# OpenTallas memory compiler (tools/mem_compiler), ASAP7 abstract view, track-aligned v2 (build_aligned_v2.py)
VERSION 5.7 ;
BUSBITCHARS "[]" ;
DIVIDERCHAR "/" ;
PROPERTYDEFINITIONS
  MACRO width INTEGER ;
  MACRO depth INTEGER ;
  MACRO banks INTEGER ;
END PROPERTYDEFINITIONS
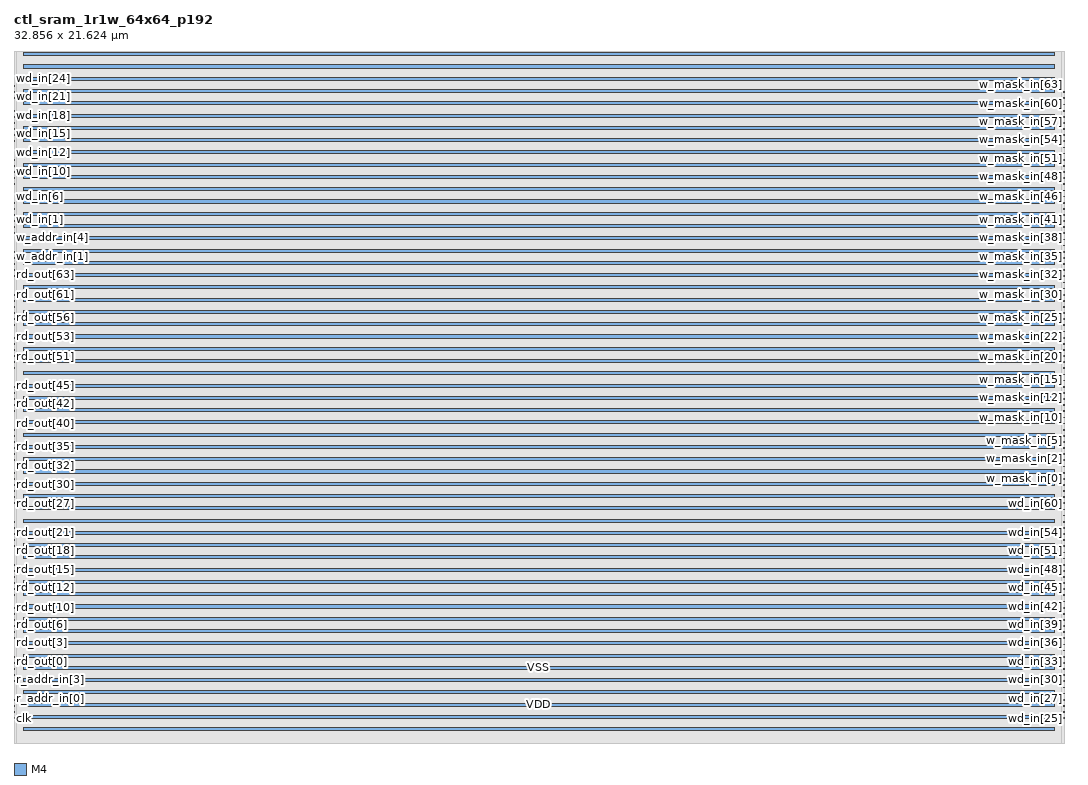
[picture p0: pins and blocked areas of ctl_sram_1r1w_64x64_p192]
MACRO ctl_sram_1r1w_64x64_p192
  PROPERTY width 64 ;
  PROPERTY depth 64 ;
  PROPERTY banks 1 ;
  FOREIGN ctl_sram_1r1w_64x64_p192 0 0 ;
  SYMMETRY X Y ;
  SIZE 32.856 BY 21.624 ;
  CLASS BLOCK ;
  PIN clk
    DIRECTION INPUT ;
    USE CLOCK ;
    SHAPE ABUTMENT ;
    PORT
      LAYER M4 ;
      RECT 0.000 0.768 0.024 0.792 ;
    END
  END clk
  PIN r_ce_in
    DIRECTION INPUT ;
    USE SIGNAL ;
    SHAPE ABUTMENT ;
    PORT
      LAYER M4 ;
      RECT 0.000 0.960 0.024 0.984 ;
    END
  END r_ce_in
  PIN r_addr_in[0]
    DIRECTION INPUT ;
    USE SIGNAL ;
    SHAPE ABUTMENT ;
    PORT
      LAYER M4 ;
      RECT 0.000 1.152 0.024 1.176 ;
    END
  END r_addr_in[0]
  PIN r_addr_in[1]
    DIRECTION INPUT ;
    USE SIGNAL ;
    SHAPE ABUTMENT ;
    PORT
      LAYER M4 ;
      RECT 0.000 1.344 0.024 1.368 ;
    END
  END r_addr_in[1]
  PIN r_addr_in[2]
    DIRECTION INPUT ;
    USE SIGNAL ;
    SHAPE ABUTMENT ;
    PORT
      LAYER M4 ;
      RECT 0.000 1.536 0.024 1.560 ;
    END
  END r_addr_in[2]
  PIN r_addr_in[3]
    DIRECTION INPUT ;
    USE SIGNAL ;
    SHAPE ABUTMENT ;
    PORT
      LAYER M4 ;
      RECT 0.000 1.728 0.024 1.752 ;
    END
  END r_addr_in[3]
  PIN r_addr_in[4]
    DIRECTION INPUT ;
    USE SIGNAL ;
    SHAPE ABUTMENT ;
    PORT
      LAYER M4 ;
      RECT 0.000 1.920 0.024 1.944 ;
    END
  END r_addr_in[4]
  PIN r_addr_in[5]
    DIRECTION INPUT ;
    USE SIGNAL ;
    SHAPE ABUTMENT ;
    PORT
      LAYER M4 ;
      RECT 0.000 2.112 0.024 2.136 ;
    END
  END r_addr_in[5]
  PIN rd_out[0]
    DIRECTION OUTPUT ;
    USE SIGNAL ;
    SHAPE ABUTMENT ;
    PORT
      LAYER M4 ;
      RECT 0.000 2.304 0.024 2.328 ;
    END
  END rd_out[0]
  PIN rd_out[1]
    DIRECTION OUTPUT ;
    USE SIGNAL ;
    SHAPE ABUTMENT ;
    PORT
      LAYER M4 ;
      RECT 0.000 2.496 0.024 2.520 ;
    END
  END rd_out[1]
  PIN rd_out[2]
    DIRECTION OUTPUT ;
    USE SIGNAL ;
    SHAPE ABUTMENT ;
    PORT
      LAYER M4 ;
      RECT 0.000 2.688 0.024 2.712 ;
    END
  END rd_out[2]
  PIN rd_out[3]
    DIRECTION OUTPUT ;
    USE SIGNAL ;
    SHAPE ABUTMENT ;
    PORT
      LAYER M4 ;
      RECT 0.000 2.880 0.024 2.904 ;
    END
  END rd_out[3]
  PIN rd_out[4]
    DIRECTION OUTPUT ;
    USE SIGNAL ;
    SHAPE ABUTMENT ;
    PORT
      LAYER M4 ;
      RECT 0.000 3.072 0.024 3.096 ;
    END
  END rd_out[4]
  PIN rd_out[5]
    DIRECTION OUTPUT ;
    USE SIGNAL ;
    SHAPE ABUTMENT ;
    PORT
      LAYER M4 ;
      RECT 0.000 3.264 0.024 3.288 ;
    END
  END rd_out[5]
  PIN rd_out[6]
    DIRECTION OUTPUT ;
    USE SIGNAL ;
    SHAPE ABUTMENT ;
    PORT
      LAYER M4 ;
      RECT 0.000 3.456 0.024 3.480 ;
    END
  END rd_out[6]
  PIN rd_out[7]
    DIRECTION OUTPUT ;
    USE SIGNAL ;
    SHAPE ABUTMENT ;
    PORT
      LAYER M4 ;
      RECT 0.000 3.648 0.024 3.672 ;
    END
  END rd_out[7]
  PIN rd_out[8]
    DIRECTION OUTPUT ;
    USE SIGNAL ;
    SHAPE ABUTMENT ;
    PORT
      LAYER M4 ;
      RECT 0.000 3.840 0.024 3.864 ;
    END
  END rd_out[8]
  PIN rd_out[9]
    DIRECTION OUTPUT ;
    USE SIGNAL ;
    SHAPE ABUTMENT ;
    PORT
      LAYER M4 ;
      RECT 0.000 4.032 0.024 4.056 ;
    END
  END rd_out[9]
  PIN rd_out[10]
    DIRECTION OUTPUT ;
    USE SIGNAL ;
    SHAPE ABUTMENT ;
    PORT
      LAYER M4 ;
      RECT 0.000 4.224 0.024 4.248 ;
    END
  END rd_out[10]
  PIN rd_out[11]
    DIRECTION OUTPUT ;
    USE SIGNAL ;
    SHAPE ABUTMENT ;
    PORT
      LAYER M4 ;
      RECT 0.000 4.416 0.024 4.440 ;
    END
  END rd_out[11]
  PIN rd_out[12]
    DIRECTION OUTPUT ;
    USE SIGNAL ;
    SHAPE ABUTMENT ;
    PORT
      LAYER M4 ;
      RECT 0.000 4.608 0.024 4.632 ;
    END
  END rd_out[12]
  PIN rd_out[13]
    DIRECTION OUTPUT ;
    USE SIGNAL ;
    SHAPE ABUTMENT ;
    PORT
      LAYER M4 ;
      RECT 0.000 4.800 0.024 4.824 ;
    END
  END rd_out[13]
  PIN rd_out[14]
    DIRECTION OUTPUT ;
    USE SIGNAL ;
    SHAPE ABUTMENT ;
    PORT
      LAYER M4 ;
      RECT 0.000 4.992 0.024 5.016 ;
    END
  END rd_out[14]
  PIN rd_out[15]
    DIRECTION OUTPUT ;
    USE SIGNAL ;
    SHAPE ABUTMENT ;
    PORT
      LAYER M4 ;
      RECT 0.000 5.184 0.024 5.208 ;
    END
  END rd_out[15]
  PIN rd_out[16]
    DIRECTION OUTPUT ;
    USE SIGNAL ;
    SHAPE ABUTMENT ;
    PORT
      LAYER M4 ;
      RECT 0.000 5.376 0.024 5.400 ;
    END
  END rd_out[16]
  PIN rd_out[17]
    DIRECTION OUTPUT ;
    USE SIGNAL ;
    SHAPE ABUTMENT ;
    PORT
      LAYER M4 ;
      RECT 0.000 5.568 0.024 5.592 ;
    END
  END rd_out[17]
  PIN rd_out[18]
    DIRECTION OUTPUT ;
    USE SIGNAL ;
    SHAPE ABUTMENT ;
    PORT
      LAYER M4 ;
      RECT 0.000 5.760 0.024 5.784 ;
    END
  END rd_out[18]
  PIN rd_out[19]
    DIRECTION OUTPUT ;
    USE SIGNAL ;
    SHAPE ABUTMENT ;
    PORT
      LAYER M4 ;
      RECT 0.000 5.952 0.024 5.976 ;
    END
  END rd_out[19]
  PIN rd_out[20]
    DIRECTION OUTPUT ;
    USE SIGNAL ;
    SHAPE ABUTMENT ;
    PORT
      LAYER M4 ;
      RECT 0.000 6.144 0.024 6.168 ;
    END
  END rd_out[20]
  PIN rd_out[21]
    DIRECTION OUTPUT ;
    USE SIGNAL ;
    SHAPE ABUTMENT ;
    PORT
      LAYER M4 ;
      RECT 0.000 6.336 0.024 6.360 ;
    END
  END rd_out[21]
  PIN rd_out[22]
    DIRECTION OUTPUT ;
    USE SIGNAL ;
    SHAPE ABUTMENT ;
    PORT
      LAYER M4 ;
      RECT 0.000 6.528 0.024 6.552 ;
    END
  END rd_out[22]
  PIN rd_out[23]
    DIRECTION OUTPUT ;
    USE SIGNAL ;
    SHAPE ABUTMENT ;
    PORT
      LAYER M4 ;
      RECT 0.000 6.720 0.024 6.744 ;
    END
  END rd_out[23]
  PIN rd_out[24]
    DIRECTION OUTPUT ;
    USE SIGNAL ;
    SHAPE ABUTMENT ;
    PORT
      LAYER M4 ;
      RECT 0.000 6.912 0.024 6.936 ;
    END
  END rd_out[24]
  PIN rd_out[25]
    DIRECTION OUTPUT ;
    USE SIGNAL ;
    SHAPE ABUTMENT ;
    PORT
      LAYER M4 ;
      RECT 0.000 7.104 0.024 7.128 ;
    END
  END rd_out[25]
  PIN rd_out[26]
    DIRECTION OUTPUT ;
    USE SIGNAL ;
    SHAPE ABUTMENT ;
    PORT
      LAYER M4 ;
      RECT 0.000 7.296 0.024 7.320 ;
    END
  END rd_out[26]
  PIN rd_out[27]
    DIRECTION OUTPUT ;
    USE SIGNAL ;
    SHAPE ABUTMENT ;
    PORT
      LAYER M4 ;
      RECT 0.000 7.488 0.024 7.512 ;
    END
  END rd_out[27]
  PIN rd_out[28]
    DIRECTION OUTPUT ;
    USE SIGNAL ;
    SHAPE ABUTMENT ;
    PORT
      LAYER M4 ;
      RECT 0.000 7.680 0.024 7.704 ;
    END
  END rd_out[28]
  PIN rd_out[29]
    DIRECTION OUTPUT ;
    USE SIGNAL ;
    SHAPE ABUTMENT ;
    PORT
      LAYER M4 ;
      RECT 0.000 7.872 0.024 7.896 ;
    END
  END rd_out[29]
  PIN rd_out[30]
    DIRECTION OUTPUT ;
    USE SIGNAL ;
    SHAPE ABUTMENT ;
    PORT
      LAYER M4 ;
      RECT 0.000 8.064 0.024 8.088 ;
    END
  END rd_out[30]
  PIN rd_out[31]
    DIRECTION OUTPUT ;
    USE SIGNAL ;
    SHAPE ABUTMENT ;
    PORT
      LAYER M4 ;
      RECT 0.000 8.256 0.024 8.280 ;
    END
  END rd_out[31]
  PIN rd_out[32]
    DIRECTION OUTPUT ;
    USE SIGNAL ;
    SHAPE ABUTMENT ;
    PORT
      LAYER M4 ;
      RECT 0.000 8.448 0.024 8.472 ;
    END
  END rd_out[32]
  PIN rd_out[33]
    DIRECTION OUTPUT ;
    USE SIGNAL ;
    SHAPE ABUTMENT ;
    PORT
      LAYER M4 ;
      RECT 0.000 8.640 0.024 8.664 ;
    END
  END rd_out[33]
  PIN rd_out[34]
    DIRECTION OUTPUT ;
    USE SIGNAL ;
    SHAPE ABUTMENT ;
    PORT
      LAYER M4 ;
      RECT 0.000 8.832 0.024 8.856 ;
    END
  END rd_out[34]
  PIN rd_out[35]
    DIRECTION OUTPUT ;
    USE SIGNAL ;
    SHAPE ABUTMENT ;
    PORT
      LAYER M4 ;
      RECT 0.000 9.024 0.024 9.048 ;
    END
  END rd_out[35]
  PIN rd_out[36]
    DIRECTION OUTPUT ;
    USE SIGNAL ;
    SHAPE ABUTMENT ;
    PORT
      LAYER M4 ;
      RECT 0.000 9.216 0.024 9.240 ;
    END
  END rd_out[36]
  PIN rd_out[37]
    DIRECTION OUTPUT ;
    USE SIGNAL ;
    SHAPE ABUTMENT ;
    PORT
      LAYER M4 ;
      RECT 0.000 9.408 0.024 9.432 ;
    END
  END rd_out[37]
  PIN rd_out[38]
    DIRECTION OUTPUT ;
    USE SIGNAL ;
    SHAPE ABUTMENT ;
    PORT
      LAYER M4 ;
      RECT 0.000 9.600 0.024 9.624 ;
    END
  END rd_out[38]
  PIN rd_out[39]
    DIRECTION OUTPUT ;
    USE SIGNAL ;
    SHAPE ABUTMENT ;
    PORT
      LAYER M4 ;
      RECT 0.000 9.792 0.024 9.816 ;
    END
  END rd_out[39]
  PIN rd_out[40]
    DIRECTION OUTPUT ;
    USE SIGNAL ;
    SHAPE ABUTMENT ;
    PORT
      LAYER M4 ;
      RECT 0.000 9.984 0.024 10.008 ;
    END
  END rd_out[40]
  PIN rd_out[41]
    DIRECTION OUTPUT ;
    USE SIGNAL ;
    SHAPE ABUTMENT ;
    PORT
      LAYER M4 ;
      RECT 0.000 10.176 0.024 10.200 ;
    END
  END rd_out[41]
  PIN rd_out[42]
    DIRECTION OUTPUT ;
    USE SIGNAL ;
    SHAPE ABUTMENT ;
    PORT
      LAYER M4 ;
      RECT 0.000 10.368 0.024 10.392 ;
    END
  END rd_out[42]
  PIN rd_out[43]
    DIRECTION OUTPUT ;
    USE SIGNAL ;
    SHAPE ABUTMENT ;
    PORT
      LAYER M4 ;
      RECT 0.000 10.560 0.024 10.584 ;
    END
  END rd_out[43]
  PIN rd_out[44]
    DIRECTION OUTPUT ;
    USE SIGNAL ;
    SHAPE ABUTMENT ;
    PORT
      LAYER M4 ;
      RECT 0.000 10.752 0.024 10.776 ;
    END
  END rd_out[44]
  PIN rd_out[45]
    DIRECTION OUTPUT ;
    USE SIGNAL ;
    SHAPE ABUTMENT ;
    PORT
      LAYER M4 ;
      RECT 0.000 10.944 0.024 10.968 ;
    END
  END rd_out[45]
  PIN rd_out[46]
    DIRECTION OUTPUT ;
    USE SIGNAL ;
    SHAPE ABUTMENT ;
    PORT
      LAYER M4 ;
      RECT 0.000 11.136 0.024 11.160 ;
    END
  END rd_out[46]
  PIN rd_out[47]
    DIRECTION OUTPUT ;
    USE SIGNAL ;
    SHAPE ABUTMENT ;
    PORT
      LAYER M4 ;
      RECT 0.000 11.328 0.024 11.352 ;
    END
  END rd_out[47]
  PIN rd_out[48]
    DIRECTION OUTPUT ;
    USE SIGNAL ;
    SHAPE ABUTMENT ;
    PORT
      LAYER M4 ;
      RECT 0.000 11.520 0.024 11.544 ;
    END
  END rd_out[48]
  PIN rd_out[49]
    DIRECTION OUTPUT ;
    USE SIGNAL ;
    SHAPE ABUTMENT ;
    PORT
      LAYER M4 ;
      RECT 0.000 11.712 0.024 11.736 ;
    END
  END rd_out[49]
  PIN rd_out[50]
    DIRECTION OUTPUT ;
    USE SIGNAL ;
    SHAPE ABUTMENT ;
    PORT
      LAYER M4 ;
      RECT 0.000 11.904 0.024 11.928 ;
    END
  END rd_out[50]
  PIN rd_out[51]
    DIRECTION OUTPUT ;
    USE SIGNAL ;
    SHAPE ABUTMENT ;
    PORT
      LAYER M4 ;
      RECT 0.000 12.096 0.024 12.120 ;
    END
  END rd_out[51]
  PIN rd_out[52]
    DIRECTION OUTPUT ;
    USE SIGNAL ;
    SHAPE ABUTMENT ;
    PORT
      LAYER M4 ;
      RECT 0.000 12.288 0.024 12.312 ;
    END
  END rd_out[52]
  PIN rd_out[53]
    DIRECTION OUTPUT ;
    USE SIGNAL ;
    SHAPE ABUTMENT ;
    PORT
      LAYER M4 ;
      RECT 0.000 12.480 0.024 12.504 ;
    END
  END rd_out[53]
  PIN rd_out[54]
    DIRECTION OUTPUT ;
    USE SIGNAL ;
    SHAPE ABUTMENT ;
    PORT
      LAYER M4 ;
      RECT 0.000 12.672 0.024 12.696 ;
    END
  END rd_out[54]
  PIN rd_out[55]
    DIRECTION OUTPUT ;
    USE SIGNAL ;
    SHAPE ABUTMENT ;
    PORT
      LAYER M4 ;
      RECT 0.000 12.864 0.024 12.888 ;
    END
  END rd_out[55]
  PIN rd_out[56]
    DIRECTION OUTPUT ;
    USE SIGNAL ;
    SHAPE ABUTMENT ;
    PORT
      LAYER M4 ;
      RECT 0.000 13.056 0.024 13.080 ;
    END
  END rd_out[56]
  PIN rd_out[57]
    DIRECTION OUTPUT ;
    USE SIGNAL ;
    SHAPE ABUTMENT ;
    PORT
      LAYER M4 ;
      RECT 0.000 13.248 0.024 13.272 ;
    END
  END rd_out[57]
  PIN rd_out[58]
    DIRECTION OUTPUT ;
    USE SIGNAL ;
    SHAPE ABUTMENT ;
    PORT
      LAYER M4 ;
      RECT 0.000 13.440 0.024 13.464 ;
    END
  END rd_out[58]
  PIN rd_out[59]
    DIRECTION OUTPUT ;
    USE SIGNAL ;
    SHAPE ABUTMENT ;
    PORT
      LAYER M4 ;
      RECT 0.000 13.632 0.024 13.656 ;
    END
  END rd_out[59]
  PIN rd_out[60]
    DIRECTION OUTPUT ;
    USE SIGNAL ;
    SHAPE ABUTMENT ;
    PORT
      LAYER M4 ;
      RECT 0.000 13.824 0.024 13.848 ;
    END
  END rd_out[60]
  PIN rd_out[61]
    DIRECTION OUTPUT ;
    USE SIGNAL ;
    SHAPE ABUTMENT ;
    PORT
      LAYER M4 ;
      RECT 0.000 14.016 0.024 14.040 ;
    END
  END rd_out[61]
  PIN rd_out[62]
    DIRECTION OUTPUT ;
    USE SIGNAL ;
    SHAPE ABUTMENT ;
    PORT
      LAYER M4 ;
      RECT 0.000 14.208 0.024 14.232 ;
    END
  END rd_out[62]
  PIN rd_out[63]
    DIRECTION OUTPUT ;
    USE SIGNAL ;
    SHAPE ABUTMENT ;
    PORT
      LAYER M4 ;
      RECT 0.000 14.400 0.024 14.424 ;
    END
  END rd_out[63]
  PIN w_ce_in
    DIRECTION INPUT ;
    USE SIGNAL ;
    SHAPE ABUTMENT ;
    PORT
      LAYER M4 ;
      RECT 0.000 14.592 0.024 14.616 ;
    END
  END w_ce_in
  PIN w_addr_in[0]
    DIRECTION INPUT ;
    USE SIGNAL ;
    SHAPE ABUTMENT ;
    PORT
      LAYER M4 ;
      RECT 0.000 14.784 0.024 14.808 ;
    END
  END w_addr_in[0]
  PIN w_addr_in[1]
    DIRECTION INPUT ;
    USE SIGNAL ;
    SHAPE ABUTMENT ;
    PORT
      LAYER M4 ;
      RECT 0.000 14.976 0.024 15.000 ;
    END
  END w_addr_in[1]
  PIN w_addr_in[2]
    DIRECTION INPUT ;
    USE SIGNAL ;
    SHAPE ABUTMENT ;
    PORT
      LAYER M4 ;
      RECT 0.000 15.168 0.024 15.192 ;
    END
  END w_addr_in[2]
  PIN w_addr_in[3]
    DIRECTION INPUT ;
    USE SIGNAL ;
    SHAPE ABUTMENT ;
    PORT
      LAYER M4 ;
      RECT 0.000 15.360 0.024 15.384 ;
    END
  END w_addr_in[3]
  PIN w_addr_in[4]
    DIRECTION INPUT ;
    USE SIGNAL ;
    SHAPE ABUTMENT ;
    PORT
      LAYER M4 ;
      RECT 0.000 15.552 0.024 15.576 ;
    END
  END w_addr_in[4]
  PIN w_addr_in[5]
    DIRECTION INPUT ;
    USE SIGNAL ;
    SHAPE ABUTMENT ;
    PORT
      LAYER M4 ;
      RECT 0.000 15.744 0.024 15.768 ;
    END
  END w_addr_in[5]
  PIN wd_in[0]
    DIRECTION INPUT ;
    USE SIGNAL ;
    SHAPE ABUTMENT ;
    PORT
      LAYER M4 ;
      RECT 0.000 15.936 0.024 15.960 ;
    END
  END wd_in[0]
  PIN wd_in[1]
    DIRECTION INPUT ;
    USE SIGNAL ;
    SHAPE ABUTMENT ;
    PORT
      LAYER M4 ;
      RECT 0.000 16.128 0.024 16.152 ;
    END
  END wd_in[1]
  PIN wd_in[2]
    DIRECTION INPUT ;
    USE SIGNAL ;
    SHAPE ABUTMENT ;
    PORT
      LAYER M4 ;
      RECT 0.000 16.320 0.024 16.344 ;
    END
  END wd_in[2]
  PIN wd_in[3]
    DIRECTION INPUT ;
    USE SIGNAL ;
    SHAPE ABUTMENT ;
    PORT
      LAYER M4 ;
      RECT 0.000 16.512 0.024 16.536 ;
    END
  END wd_in[3]
  PIN wd_in[4]
    DIRECTION INPUT ;
    USE SIGNAL ;
    SHAPE ABUTMENT ;
    PORT
      LAYER M4 ;
      RECT 0.000 16.704 0.024 16.728 ;
    END
  END wd_in[4]
  PIN wd_in[5]
    DIRECTION INPUT ;
    USE SIGNAL ;
    SHAPE ABUTMENT ;
    PORT
      LAYER M4 ;
      RECT 0.000 16.896 0.024 16.920 ;
    END
  END wd_in[5]
  PIN wd_in[6]
    DIRECTION INPUT ;
    USE SIGNAL ;
    SHAPE ABUTMENT ;
    PORT
      LAYER M4 ;
      RECT 0.000 17.088 0.024 17.112 ;
    END
  END wd_in[6]
  PIN wd_in[7]
    DIRECTION INPUT ;
    USE SIGNAL ;
    SHAPE ABUTMENT ;
    PORT
      LAYER M4 ;
      RECT 0.000 17.280 0.024 17.304 ;
    END
  END wd_in[7]
  PIN wd_in[8]
    DIRECTION INPUT ;
    USE SIGNAL ;
    SHAPE ABUTMENT ;
    PORT
      LAYER M4 ;
      RECT 0.000 17.472 0.024 17.496 ;
    END
  END wd_in[8]
  PIN wd_in[9]
    DIRECTION INPUT ;
    USE SIGNAL ;
    SHAPE ABUTMENT ;
    PORT
      LAYER M4 ;
      RECT 0.000 17.664 0.024 17.688 ;
    END
  END wd_in[9]
  PIN wd_in[10]
    DIRECTION INPUT ;
    USE SIGNAL ;
    SHAPE ABUTMENT ;
    PORT
      LAYER M4 ;
      RECT 0.000 17.856 0.024 17.880 ;
    END
  END wd_in[10]
  PIN wd_in[11]
    DIRECTION INPUT ;
    USE SIGNAL ;
    SHAPE ABUTMENT ;
    PORT
      LAYER M4 ;
      RECT 0.000 18.048 0.024 18.072 ;
    END
  END wd_in[11]
  PIN wd_in[12]
    DIRECTION INPUT ;
    USE SIGNAL ;
    SHAPE ABUTMENT ;
    PORT
      LAYER M4 ;
      RECT 0.000 18.240 0.024 18.264 ;
    END
  END wd_in[12]
  PIN wd_in[13]
    DIRECTION INPUT ;
    USE SIGNAL ;
    SHAPE ABUTMENT ;
    PORT
      LAYER M4 ;
      RECT 0.000 18.432 0.024 18.456 ;
    END
  END wd_in[13]
  PIN wd_in[14]
    DIRECTION INPUT ;
    USE SIGNAL ;
    SHAPE ABUTMENT ;
    PORT
      LAYER M4 ;
      RECT 0.000 18.624 0.024 18.648 ;
    END
  END wd_in[14]
  PIN wd_in[15]
    DIRECTION INPUT ;
    USE SIGNAL ;
    SHAPE ABUTMENT ;
    PORT
      LAYER M4 ;
      RECT 0.000 18.816 0.024 18.840 ;
    END
  END wd_in[15]
  PIN wd_in[16]
    DIRECTION INPUT ;
    USE SIGNAL ;
    SHAPE ABUTMENT ;
    PORT
      LAYER M4 ;
      RECT 0.000 19.008 0.024 19.032 ;
    END
  END wd_in[16]
  PIN wd_in[17]
    DIRECTION INPUT ;
    USE SIGNAL ;
    SHAPE ABUTMENT ;
    PORT
      LAYER M4 ;
      RECT 0.000 19.200 0.024 19.224 ;
    END
  END wd_in[17]
  PIN wd_in[18]
    DIRECTION INPUT ;
    USE SIGNAL ;
    SHAPE ABUTMENT ;
    PORT
      LAYER M4 ;
      RECT 0.000 19.392 0.024 19.416 ;
    END
  END wd_in[18]
  PIN wd_in[19]
    DIRECTION INPUT ;
    USE SIGNAL ;
    SHAPE ABUTMENT ;
    PORT
      LAYER M4 ;
      RECT 0.000 19.584 0.024 19.608 ;
    END
  END wd_in[19]
  PIN wd_in[20]
    DIRECTION INPUT ;
    USE SIGNAL ;
    SHAPE ABUTMENT ;
    PORT
      LAYER M4 ;
      RECT 0.000 19.776 0.024 19.800 ;
    END
  END wd_in[20]
  PIN wd_in[21]
    DIRECTION INPUT ;
    USE SIGNAL ;
    SHAPE ABUTMENT ;
    PORT
      LAYER M4 ;
      RECT 0.000 19.968 0.024 19.992 ;
    END
  END wd_in[21]
  PIN wd_in[22]
    DIRECTION INPUT ;
    USE SIGNAL ;
    SHAPE ABUTMENT ;
    PORT
      LAYER M4 ;
      RECT 0.000 20.160 0.024 20.184 ;
    END
  END wd_in[22]
  PIN wd_in[23]
    DIRECTION INPUT ;
    USE SIGNAL ;
    SHAPE ABUTMENT ;
    PORT
      LAYER M4 ;
      RECT 0.000 20.352 0.024 20.376 ;
    END
  END wd_in[23]
  PIN wd_in[24]
    DIRECTION INPUT ;
    USE SIGNAL ;
    SHAPE ABUTMENT ;
    PORT
      LAYER M4 ;
      RECT 0.000 20.544 0.024 20.568 ;
    END
  END wd_in[24]
  PIN wd_in[25]
    DIRECTION INPUT ;
    USE SIGNAL ;
    SHAPE ABUTMENT ;
    PORT
      LAYER M4 ;
      RECT 32.832 0.768 32.856 0.792 ;
    END
  END wd_in[25]
  PIN wd_in[26]
    DIRECTION INPUT ;
    USE SIGNAL ;
    SHAPE ABUTMENT ;
    PORT
      LAYER M4 ;
      RECT 32.832 0.960 32.856 0.984 ;
    END
  END wd_in[26]
  PIN wd_in[27]
    DIRECTION INPUT ;
    USE SIGNAL ;
    SHAPE ABUTMENT ;
    PORT
      LAYER M4 ;
      RECT 32.832 1.152 32.856 1.176 ;
    END
  END wd_in[27]
  PIN wd_in[28]
    DIRECTION INPUT ;
    USE SIGNAL ;
    SHAPE ABUTMENT ;
    PORT
      LAYER M4 ;
      RECT 32.832 1.344 32.856 1.368 ;
    END
  END wd_in[28]
  PIN wd_in[29]
    DIRECTION INPUT ;
    USE SIGNAL ;
    SHAPE ABUTMENT ;
    PORT
      LAYER M4 ;
      RECT 32.832 1.536 32.856 1.560 ;
    END
  END wd_in[29]
  PIN wd_in[30]
    DIRECTION INPUT ;
    USE SIGNAL ;
    SHAPE ABUTMENT ;
    PORT
      LAYER M4 ;
      RECT 32.832 1.728 32.856 1.752 ;
    END
  END wd_in[30]
  PIN wd_in[31]
    DIRECTION INPUT ;
    USE SIGNAL ;
    SHAPE ABUTMENT ;
    PORT
      LAYER M4 ;
      RECT 32.832 1.920 32.856 1.944 ;
    END
  END wd_in[31]
  PIN wd_in[32]
    DIRECTION INPUT ;
    USE SIGNAL ;
    SHAPE ABUTMENT ;
    PORT
      LAYER M4 ;
      RECT 32.832 2.112 32.856 2.136 ;
    END
  END wd_in[32]
  PIN wd_in[33]
    DIRECTION INPUT ;
    USE SIGNAL ;
    SHAPE ABUTMENT ;
    PORT
      LAYER M4 ;
      RECT 32.832 2.304 32.856 2.328 ;
    END
  END wd_in[33]
  PIN wd_in[34]
    DIRECTION INPUT ;
    USE SIGNAL ;
    SHAPE ABUTMENT ;
    PORT
      LAYER M4 ;
      RECT 32.832 2.496 32.856 2.520 ;
    END
  END wd_in[34]
  PIN wd_in[35]
    DIRECTION INPUT ;
    USE SIGNAL ;
    SHAPE ABUTMENT ;
    PORT
      LAYER M4 ;
      RECT 32.832 2.688 32.856 2.712 ;
    END
  END wd_in[35]
  PIN wd_in[36]
    DIRECTION INPUT ;
    USE SIGNAL ;
    SHAPE ABUTMENT ;
    PORT
      LAYER M4 ;
      RECT 32.832 2.880 32.856 2.904 ;
    END
  END wd_in[36]
  PIN wd_in[37]
    DIRECTION INPUT ;
    USE SIGNAL ;
    SHAPE ABUTMENT ;
    PORT
      LAYER M4 ;
      RECT 32.832 3.072 32.856 3.096 ;
    END
  END wd_in[37]
  PIN wd_in[38]
    DIRECTION INPUT ;
    USE SIGNAL ;
    SHAPE ABUTMENT ;
    PORT
      LAYER M4 ;
      RECT 32.832 3.264 32.856 3.288 ;
    END
  END wd_in[38]
  PIN wd_in[39]
    DIRECTION INPUT ;
    USE SIGNAL ;
    SHAPE ABUTMENT ;
    PORT
      LAYER M4 ;
      RECT 32.832 3.456 32.856 3.480 ;
    END
  END wd_in[39]
  PIN wd_in[40]
    DIRECTION INPUT ;
    USE SIGNAL ;
    SHAPE ABUTMENT ;
    PORT
      LAYER M4 ;
      RECT 32.832 3.648 32.856 3.672 ;
    END
  END wd_in[40]
  PIN wd_in[41]
    DIRECTION INPUT ;
    USE SIGNAL ;
    SHAPE ABUTMENT ;
    PORT
      LAYER M4 ;
      RECT 32.832 3.840 32.856 3.864 ;
    END
  END wd_in[41]
  PIN wd_in[42]
    DIRECTION INPUT ;
    USE SIGNAL ;
    SHAPE ABUTMENT ;
    PORT
      LAYER M4 ;
      RECT 32.832 4.032 32.856 4.056 ;
    END
  END wd_in[42]
  PIN wd_in[43]
    DIRECTION INPUT ;
    USE SIGNAL ;
    SHAPE ABUTMENT ;
    PORT
      LAYER M4 ;
      RECT 32.832 4.224 32.856 4.248 ;
    END
  END wd_in[43]
  PIN wd_in[44]
    DIRECTION INPUT ;
    USE SIGNAL ;
    SHAPE ABUTMENT ;
    PORT
      LAYER M4 ;
      RECT 32.832 4.416 32.856 4.440 ;
    END
  END wd_in[44]
  PIN wd_in[45]
    DIRECTION INPUT ;
    USE SIGNAL ;
    SHAPE ABUTMENT ;
    PORT
      LAYER M4 ;
      RECT 32.832 4.608 32.856 4.632 ;
    END
  END wd_in[45]
  PIN wd_in[46]
    DIRECTION INPUT ;
    USE SIGNAL ;
    SHAPE ABUTMENT ;
    PORT
      LAYER M4 ;
      RECT 32.832 4.800 32.856 4.824 ;
    END
  END wd_in[46]
  PIN wd_in[47]
    DIRECTION INPUT ;
    USE SIGNAL ;
    SHAPE ABUTMENT ;
    PORT
      LAYER M4 ;
      RECT 32.832 4.992 32.856 5.016 ;
    END
  END wd_in[47]
  PIN wd_in[48]
    DIRECTION INPUT ;
    USE SIGNAL ;
    SHAPE ABUTMENT ;
    PORT
      LAYER M4 ;
      RECT 32.832 5.184 32.856 5.208 ;
    END
  END wd_in[48]
  PIN wd_in[49]
    DIRECTION INPUT ;
    USE SIGNAL ;
    SHAPE ABUTMENT ;
    PORT
      LAYER M4 ;
      RECT 32.832 5.376 32.856 5.400 ;
    END
  END wd_in[49]
  PIN wd_in[50]
    DIRECTION INPUT ;
    USE SIGNAL ;
    SHAPE ABUTMENT ;
    PORT
      LAYER M4 ;
      RECT 32.832 5.568 32.856 5.592 ;
    END
  END wd_in[50]
  PIN wd_in[51]
    DIRECTION INPUT ;
    USE SIGNAL ;
    SHAPE ABUTMENT ;
    PORT
      LAYER M4 ;
      RECT 32.832 5.760 32.856 5.784 ;
    END
  END wd_in[51]
  PIN wd_in[52]
    DIRECTION INPUT ;
    USE SIGNAL ;
    SHAPE ABUTMENT ;
    PORT
      LAYER M4 ;
      RECT 32.832 5.952 32.856 5.976 ;
    END
  END wd_in[52]
  PIN wd_in[53]
    DIRECTION INPUT ;
    USE SIGNAL ;
    SHAPE ABUTMENT ;
    PORT
      LAYER M4 ;
      RECT 32.832 6.144 32.856 6.168 ;
    END
  END wd_in[53]
  PIN wd_in[54]
    DIRECTION INPUT ;
    USE SIGNAL ;
    SHAPE ABUTMENT ;
    PORT
      LAYER M4 ;
      RECT 32.832 6.336 32.856 6.360 ;
    END
  END wd_in[54]
  PIN wd_in[55]
    DIRECTION INPUT ;
    USE SIGNAL ;
    SHAPE ABUTMENT ;
    PORT
      LAYER M4 ;
      RECT 32.832 6.528 32.856 6.552 ;
    END
  END wd_in[55]
  PIN wd_in[56]
    DIRECTION INPUT ;
    USE SIGNAL ;
    SHAPE ABUTMENT ;
    PORT
      LAYER M4 ;
      RECT 32.832 6.720 32.856 6.744 ;
    END
  END wd_in[56]
  PIN wd_in[57]
    DIRECTION INPUT ;
    USE SIGNAL ;
    SHAPE ABUTMENT ;
    PORT
      LAYER M4 ;
      RECT 32.832 6.912 32.856 6.936 ;
    END
  END wd_in[57]
  PIN wd_in[58]
    DIRECTION INPUT ;
    USE SIGNAL ;
    SHAPE ABUTMENT ;
    PORT
      LAYER M4 ;
      RECT 32.832 7.104 32.856 7.128 ;
    END
  END wd_in[58]
  PIN wd_in[59]
    DIRECTION INPUT ;
    USE SIGNAL ;
    SHAPE ABUTMENT ;
    PORT
      LAYER M4 ;
      RECT 32.832 7.296 32.856 7.320 ;
    END
  END wd_in[59]
  PIN wd_in[60]
    DIRECTION INPUT ;
    USE SIGNAL ;
    SHAPE ABUTMENT ;
    PORT
      LAYER M4 ;
      RECT 32.832 7.488 32.856 7.512 ;
    END
  END wd_in[60]
  PIN wd_in[61]
    DIRECTION INPUT ;
    USE SIGNAL ;
    SHAPE ABUTMENT ;
    PORT
      LAYER M4 ;
      RECT 32.832 7.680 32.856 7.704 ;
    END
  END wd_in[61]
  PIN wd_in[62]
    DIRECTION INPUT ;
    USE SIGNAL ;
    SHAPE ABUTMENT ;
    PORT
      LAYER M4 ;
      RECT 32.832 7.872 32.856 7.896 ;
    END
  END wd_in[62]
  PIN wd_in[63]
    DIRECTION INPUT ;
    USE SIGNAL ;
    SHAPE ABUTMENT ;
    PORT
      LAYER M4 ;
      RECT 32.832 8.064 32.856 8.088 ;
    END
  END wd_in[63]
  PIN w_mask_in[0]
    DIRECTION INPUT ;
    USE SIGNAL ;
    SHAPE ABUTMENT ;
    PORT
      LAYER M4 ;
      RECT 32.832 8.256 32.856 8.280 ;
    END
  END w_mask_in[0]
  PIN w_mask_in[1]
    DIRECTION INPUT ;
    USE SIGNAL ;
    SHAPE ABUTMENT ;
    PORT
      LAYER M4 ;
      RECT 32.832 8.448 32.856 8.472 ;
    END
  END w_mask_in[1]
  PIN w_mask_in[2]
    DIRECTION INPUT ;
    USE SIGNAL ;
    SHAPE ABUTMENT ;
    PORT
      LAYER M4 ;
      RECT 32.832 8.640 32.856 8.664 ;
    END
  END w_mask_in[2]
  PIN w_mask_in[3]
    DIRECTION INPUT ;
    USE SIGNAL ;
    SHAPE ABUTMENT ;
    PORT
      LAYER M4 ;
      RECT 32.832 8.832 32.856 8.856 ;
    END
  END w_mask_in[3]
  PIN w_mask_in[4]
    DIRECTION INPUT ;
    USE SIGNAL ;
    SHAPE ABUTMENT ;
    PORT
      LAYER M4 ;
      RECT 32.832 9.024 32.856 9.048 ;
    END
  END w_mask_in[4]
  PIN w_mask_in[5]
    DIRECTION INPUT ;
    USE SIGNAL ;
    SHAPE ABUTMENT ;
    PORT
      LAYER M4 ;
      RECT 32.832 9.216 32.856 9.240 ;
    END
  END w_mask_in[5]
  PIN w_mask_in[6]
    DIRECTION INPUT ;
    USE SIGNAL ;
    SHAPE ABUTMENT ;
    PORT
      LAYER M4 ;
      RECT 32.832 9.408 32.856 9.432 ;
    END
  END w_mask_in[6]
  PIN w_mask_in[7]
    DIRECTION INPUT ;
    USE SIGNAL ;
    SHAPE ABUTMENT ;
    PORT
      LAYER M4 ;
      RECT 32.832 9.600 32.856 9.624 ;
    END
  END w_mask_in[7]
  PIN w_mask_in[8]
    DIRECTION INPUT ;
    USE SIGNAL ;
    SHAPE ABUTMENT ;
    PORT
      LAYER M4 ;
      RECT 32.832 9.792 32.856 9.816 ;
    END
  END w_mask_in[8]
  PIN w_mask_in[9]
    DIRECTION INPUT ;
    USE SIGNAL ;
    SHAPE ABUTMENT ;
    PORT
      LAYER M4 ;
      RECT 32.832 9.984 32.856 10.008 ;
    END
  END w_mask_in[9]
  PIN w_mask_in[10]
    DIRECTION INPUT ;
    USE SIGNAL ;
    SHAPE ABUTMENT ;
    PORT
      LAYER M4 ;
      RECT 32.832 10.176 32.856 10.200 ;
    END
  END w_mask_in[10]
  PIN w_mask_in[11]
    DIRECTION INPUT ;
    USE SIGNAL ;
    SHAPE ABUTMENT ;
    PORT
      LAYER M4 ;
      RECT 32.832 10.368 32.856 10.392 ;
    END
  END w_mask_in[11]
  PIN w_mask_in[12]
    DIRECTION INPUT ;
    USE SIGNAL ;
    SHAPE ABUTMENT ;
    PORT
      LAYER M4 ;
      RECT 32.832 10.560 32.856 10.584 ;
    END
  END w_mask_in[12]
  PIN w_mask_in[13]
    DIRECTION INPUT ;
    USE SIGNAL ;
    SHAPE ABUTMENT ;
    PORT
      LAYER M4 ;
      RECT 32.832 10.752 32.856 10.776 ;
    END
  END w_mask_in[13]
  PIN w_mask_in[14]
    DIRECTION INPUT ;
    USE SIGNAL ;
    SHAPE ABUTMENT ;
    PORT
      LAYER M4 ;
      RECT 32.832 10.944 32.856 10.968 ;
    END
  END w_mask_in[14]
  PIN w_mask_in[15]
    DIRECTION INPUT ;
    USE SIGNAL ;
    SHAPE ABUTMENT ;
    PORT
      LAYER M4 ;
      RECT 32.832 11.136 32.856 11.160 ;
    END
  END w_mask_in[15]
  PIN w_mask_in[16]
    DIRECTION INPUT ;
    USE SIGNAL ;
    SHAPE ABUTMENT ;
    PORT
      LAYER M4 ;
      RECT 32.832 11.328 32.856 11.352 ;
    END
  END w_mask_in[16]
  PIN w_mask_in[17]
    DIRECTION INPUT ;
    USE SIGNAL ;
    SHAPE ABUTMENT ;
    PORT
      LAYER M4 ;
      RECT 32.832 11.520 32.856 11.544 ;
    END
  END w_mask_in[17]
  PIN w_mask_in[18]
    DIRECTION INPUT ;
    USE SIGNAL ;
    SHAPE ABUTMENT ;
    PORT
      LAYER M4 ;
      RECT 32.832 11.712 32.856 11.736 ;
    END
  END w_mask_in[18]
  PIN w_mask_in[19]
    DIRECTION INPUT ;
    USE SIGNAL ;
    SHAPE ABUTMENT ;
    PORT
      LAYER M4 ;
      RECT 32.832 11.904 32.856 11.928 ;
    END
  END w_mask_in[19]
  PIN w_mask_in[20]
    DIRECTION INPUT ;
    USE SIGNAL ;
    SHAPE ABUTMENT ;
    PORT
      LAYER M4 ;
      RECT 32.832 12.096 32.856 12.120 ;
    END
  END w_mask_in[20]
  PIN w_mask_in[21]
    DIRECTION INPUT ;
    USE SIGNAL ;
    SHAPE ABUTMENT ;
    PORT
      LAYER M4 ;
      RECT 32.832 12.288 32.856 12.312 ;
    END
  END w_mask_in[21]
  PIN w_mask_in[22]
    DIRECTION INPUT ;
    USE SIGNAL ;
    SHAPE ABUTMENT ;
    PORT
      LAYER M4 ;
      RECT 32.832 12.480 32.856 12.504 ;
    END
  END w_mask_in[22]
  PIN w_mask_in[23]
    DIRECTION INPUT ;
    USE SIGNAL ;
    SHAPE ABUTMENT ;
    PORT
      LAYER M4 ;
      RECT 32.832 12.672 32.856 12.696 ;
    END
  END w_mask_in[23]
  PIN w_mask_in[24]
    DIRECTION INPUT ;
    USE SIGNAL ;
    SHAPE ABUTMENT ;
    PORT
      LAYER M4 ;
      RECT 32.832 12.864 32.856 12.888 ;
    END
  END w_mask_in[24]
  PIN w_mask_in[25]
    DIRECTION INPUT ;
    USE SIGNAL ;
    SHAPE ABUTMENT ;
    PORT
      LAYER M4 ;
      RECT 32.832 13.056 32.856 13.080 ;
    END
  END w_mask_in[25]
  PIN w_mask_in[26]
    DIRECTION INPUT ;
    USE SIGNAL ;
    SHAPE ABUTMENT ;
    PORT
      LAYER M4 ;
      RECT 32.832 13.248 32.856 13.272 ;
    END
  END w_mask_in[26]
  PIN w_mask_in[27]
    DIRECTION INPUT ;
    USE SIGNAL ;
    SHAPE ABUTMENT ;
    PORT
      LAYER M4 ;
      RECT 32.832 13.440 32.856 13.464 ;
    END
  END w_mask_in[27]
  PIN w_mask_in[28]
    DIRECTION INPUT ;
    USE SIGNAL ;
    SHAPE ABUTMENT ;
    PORT
      LAYER M4 ;
      RECT 32.832 13.632 32.856 13.656 ;
    END
  END w_mask_in[28]
  PIN w_mask_in[29]
    DIRECTION INPUT ;
    USE SIGNAL ;
    SHAPE ABUTMENT ;
    PORT
      LAYER M4 ;
      RECT 32.832 13.824 32.856 13.848 ;
    END
  END w_mask_in[29]
  PIN w_mask_in[30]
    DIRECTION INPUT ;
    USE SIGNAL ;
    SHAPE ABUTMENT ;
    PORT
      LAYER M4 ;
      RECT 32.832 14.016 32.856 14.040 ;
    END
  END w_mask_in[30]
  PIN w_mask_in[31]
    DIRECTION INPUT ;
    USE SIGNAL ;
    SHAPE ABUTMENT ;
    PORT
      LAYER M4 ;
      RECT 32.832 14.208 32.856 14.232 ;
    END
  END w_mask_in[31]
  PIN w_mask_in[32]
    DIRECTION INPUT ;
    USE SIGNAL ;
    SHAPE ABUTMENT ;
    PORT
      LAYER M4 ;
      RECT 32.832 14.400 32.856 14.424 ;
    END
  END w_mask_in[32]
  PIN w_mask_in[33]
    DIRECTION INPUT ;
    USE SIGNAL ;
    SHAPE ABUTMENT ;
    PORT
      LAYER M4 ;
      RECT 32.832 14.592 32.856 14.616 ;
    END
  END w_mask_in[33]
  PIN w_mask_in[34]
    DIRECTION INPUT ;
    USE SIGNAL ;
    SHAPE ABUTMENT ;
    PORT
      LAYER M4 ;
      RECT 32.832 14.784 32.856 14.808 ;
    END
  END w_mask_in[34]
  PIN w_mask_in[35]
    DIRECTION INPUT ;
    USE SIGNAL ;
    SHAPE ABUTMENT ;
    PORT
      LAYER M4 ;
      RECT 32.832 14.976 32.856 15.000 ;
    END
  END w_mask_in[35]
  PIN w_mask_in[36]
    DIRECTION INPUT ;
    USE SIGNAL ;
    SHAPE ABUTMENT ;
    PORT
      LAYER M4 ;
      RECT 32.832 15.168 32.856 15.192 ;
    END
  END w_mask_in[36]
  PIN w_mask_in[37]
    DIRECTION INPUT ;
    USE SIGNAL ;
    SHAPE ABUTMENT ;
    PORT
      LAYER M4 ;
      RECT 32.832 15.360 32.856 15.384 ;
    END
  END w_mask_in[37]
  PIN w_mask_in[38]
    DIRECTION INPUT ;
    USE SIGNAL ;
    SHAPE ABUTMENT ;
    PORT
      LAYER M4 ;
      RECT 32.832 15.552 32.856 15.576 ;
    END
  END w_mask_in[38]
  PIN w_mask_in[39]
    DIRECTION INPUT ;
    USE SIGNAL ;
    SHAPE ABUTMENT ;
    PORT
      LAYER M4 ;
      RECT 32.832 15.744 32.856 15.768 ;
    END
  END w_mask_in[39]
  PIN w_mask_in[40]
    DIRECTION INPUT ;
    USE SIGNAL ;
    SHAPE ABUTMENT ;
    PORT
      LAYER M4 ;
      RECT 32.832 15.936 32.856 15.960 ;
    END
  END w_mask_in[40]
  PIN w_mask_in[41]
    DIRECTION INPUT ;
    USE SIGNAL ;
    SHAPE ABUTMENT ;
    PORT
      LAYER M4 ;
      RECT 32.832 16.128 32.856 16.152 ;
    END
  END w_mask_in[41]
  PIN w_mask_in[42]
    DIRECTION INPUT ;
    USE SIGNAL ;
    SHAPE ABUTMENT ;
    PORT
      LAYER M4 ;
      RECT 32.832 16.320 32.856 16.344 ;
    END
  END w_mask_in[42]
  PIN w_mask_in[43]
    DIRECTION INPUT ;
    USE SIGNAL ;
    SHAPE ABUTMENT ;
    PORT
      LAYER M4 ;
      RECT 32.832 16.512 32.856 16.536 ;
    END
  END w_mask_in[43]
  PIN w_mask_in[44]
    DIRECTION INPUT ;
    USE SIGNAL ;
    SHAPE ABUTMENT ;
    PORT
      LAYER M4 ;
      RECT 32.832 16.704 32.856 16.728 ;
    END
  END w_mask_in[44]
  PIN w_mask_in[45]
    DIRECTION INPUT ;
    USE SIGNAL ;
    SHAPE ABUTMENT ;
    PORT
      LAYER M4 ;
      RECT 32.832 16.896 32.856 16.920 ;
    END
  END w_mask_in[45]
  PIN w_mask_in[46]
    DIRECTION INPUT ;
    USE SIGNAL ;
    SHAPE ABUTMENT ;
    PORT
      LAYER M4 ;
      RECT 32.832 17.088 32.856 17.112 ;
    END
  END w_mask_in[46]
  PIN w_mask_in[47]
    DIRECTION INPUT ;
    USE SIGNAL ;
    SHAPE ABUTMENT ;
    PORT
      LAYER M4 ;
      RECT 32.832 17.280 32.856 17.304 ;
    END
  END w_mask_in[47]
  PIN w_mask_in[48]
    DIRECTION INPUT ;
    USE SIGNAL ;
    SHAPE ABUTMENT ;
    PORT
      LAYER M4 ;
      RECT 32.832 17.472 32.856 17.496 ;
    END
  END w_mask_in[48]
  PIN w_mask_in[49]
    DIRECTION INPUT ;
    USE SIGNAL ;
    SHAPE ABUTMENT ;
    PORT
      LAYER M4 ;
      RECT 32.832 17.664 32.856 17.688 ;
    END
  END w_mask_in[49]
  PIN w_mask_in[50]
    DIRECTION INPUT ;
    USE SIGNAL ;
    SHAPE ABUTMENT ;
    PORT
      LAYER M4 ;
      RECT 32.832 17.856 32.856 17.880 ;
    END
  END w_mask_in[50]
  PIN w_mask_in[51]
    DIRECTION INPUT ;
    USE SIGNAL ;
    SHAPE ABUTMENT ;
    PORT
      LAYER M4 ;
      RECT 32.832 18.048 32.856 18.072 ;
    END
  END w_mask_in[51]
  PIN w_mask_in[52]
    DIRECTION INPUT ;
    USE SIGNAL ;
    SHAPE ABUTMENT ;
    PORT
      LAYER M4 ;
      RECT 32.832 18.240 32.856 18.264 ;
    END
  END w_mask_in[52]
  PIN w_mask_in[53]
    DIRECTION INPUT ;
    USE SIGNAL ;
    SHAPE ABUTMENT ;
    PORT
      LAYER M4 ;
      RECT 32.832 18.432 32.856 18.456 ;
    END
  END w_mask_in[53]
  PIN w_mask_in[54]
    DIRECTION INPUT ;
    USE SIGNAL ;
    SHAPE ABUTMENT ;
    PORT
      LAYER M4 ;
      RECT 32.832 18.624 32.856 18.648 ;
    END
  END w_mask_in[54]
  PIN w_mask_in[55]
    DIRECTION INPUT ;
    USE SIGNAL ;
    SHAPE ABUTMENT ;
    PORT
      LAYER M4 ;
      RECT 32.832 18.816 32.856 18.840 ;
    END
  END w_mask_in[55]
  PIN w_mask_in[56]
    DIRECTION INPUT ;
    USE SIGNAL ;
    SHAPE ABUTMENT ;
    PORT
      LAYER M4 ;
      RECT 32.832 19.008 32.856 19.032 ;
    END
  END w_mask_in[56]
  PIN w_mask_in[57]
    DIRECTION INPUT ;
    USE SIGNAL ;
    SHAPE ABUTMENT ;
    PORT
      LAYER M4 ;
      RECT 32.832 19.200 32.856 19.224 ;
    END
  END w_mask_in[57]
  PIN w_mask_in[58]
    DIRECTION INPUT ;
    USE SIGNAL ;
    SHAPE ABUTMENT ;
    PORT
      LAYER M4 ;
      RECT 32.832 19.392 32.856 19.416 ;
    END
  END w_mask_in[58]
  PIN w_mask_in[59]
    DIRECTION INPUT ;
    USE SIGNAL ;
    SHAPE ABUTMENT ;
    PORT
      LAYER M4 ;
      RECT 32.832 19.584 32.856 19.608 ;
    END
  END w_mask_in[59]
  PIN w_mask_in[60]
    DIRECTION INPUT ;
    USE SIGNAL ;
    SHAPE ABUTMENT ;
    PORT
      LAYER M4 ;
      RECT 32.832 19.776 32.856 19.800 ;
    END
  END w_mask_in[60]
  PIN w_mask_in[61]
    DIRECTION INPUT ;
    USE SIGNAL ;
    SHAPE ABUTMENT ;
    PORT
      LAYER M4 ;
      RECT 32.832 19.968 32.856 19.992 ;
    END
  END w_mask_in[61]
  PIN w_mask_in[62]
    DIRECTION INPUT ;
    USE SIGNAL ;
    SHAPE ABUTMENT ;
    PORT
      LAYER M4 ;
      RECT 32.832 20.160 32.856 20.184 ;
    END
  END w_mask_in[62]
  PIN w_mask_in[63]
    DIRECTION INPUT ;
    USE SIGNAL ;
    SHAPE ABUTMENT ;
    PORT
      LAYER M4 ;
      RECT 32.832 20.352 32.856 20.376 ;
    END
  END w_mask_in[63]
  PIN VDD
    DIRECTION INOUT ;
    USE POWER ;
    PORT
      LAYER M4 ;
      RECT 0.300 0.384 32.556 0.480 ;
      RECT 0.300 1.152 32.556 1.248 ;
      RECT 0.300 1.920 32.556 2.016 ;
      RECT 0.300 2.688 32.556 2.784 ;
      RECT 0.300 3.456 32.556 3.552 ;
      RECT 0.300 4.224 32.556 4.320 ;
      RECT 0.300 4.992 32.556 5.088 ;
      RECT 0.300 5.760 32.556 5.856 ;
      RECT 0.300 6.528 32.556 6.624 ;
      RECT 0.300 7.296 32.556 7.392 ;
      RECT 0.300 8.064 32.556 8.160 ;
      RECT 0.300 8.832 32.556 8.928 ;
      RECT 0.300 9.600 32.556 9.696 ;
      RECT 0.300 10.368 32.556 10.464 ;
      RECT 0.300 11.136 32.556 11.232 ;
      RECT 0.300 11.904 32.556 12.000 ;
      RECT 0.300 12.672 32.556 12.768 ;
      RECT 0.300 13.440 32.556 13.536 ;
      RECT 0.300 14.208 32.556 14.304 ;
      RECT 0.300 14.976 32.556 15.072 ;
      RECT 0.300 15.744 32.556 15.840 ;
      RECT 0.300 16.512 32.556 16.608 ;
      RECT 0.300 17.280 32.556 17.376 ;
      RECT 0.300 18.048 32.556 18.144 ;
      RECT 0.300 18.816 32.556 18.912 ;
      RECT 0.300 19.584 32.556 19.680 ;
      RECT 0.300 20.352 32.556 20.448 ;
      RECT 0.300 21.120 32.556 21.216 ;
    END
  END VDD
  PIN VSS
    DIRECTION INOUT ;
    USE GROUND ;
    PORT
      LAYER M4 ;
      RECT 0.300 0.768 32.556 0.864 ;
      RECT 0.300 1.536 32.556 1.632 ;
      RECT 0.300 2.304 32.556 2.400 ;
      RECT 0.300 3.072 32.556 3.168 ;
      RECT 0.300 3.840 32.556 3.936 ;
      RECT 0.300 4.608 32.556 4.704 ;
      RECT 0.300 5.376 32.556 5.472 ;
      RECT 0.300 6.144 32.556 6.240 ;
      RECT 0.300 6.912 32.556 7.008 ;
      RECT 0.300 7.680 32.556 7.776 ;
      RECT 0.300 8.448 32.556 8.544 ;
      RECT 0.300 9.216 32.556 9.312 ;
      RECT 0.300 9.984 32.556 10.080 ;
      RECT 0.300 10.752 32.556 10.848 ;
      RECT 0.300 11.520 32.556 11.616 ;
      RECT 0.300 12.288 32.556 12.384 ;
      RECT 0.300 13.056 32.556 13.152 ;
      RECT 0.300 13.824 32.556 13.920 ;
      RECT 0.300 14.592 32.556 14.688 ;
      RECT 0.300 15.360 32.556 15.456 ;
      RECT 0.300 16.128 32.556 16.224 ;
      RECT 0.300 16.896 32.556 16.992 ;
      RECT 0.300 17.664 32.556 17.760 ;
      RECT 0.300 18.432 32.556 18.528 ;
      RECT 0.300 19.200 32.556 19.296 ;
      RECT 0.300 19.968 32.556 20.064 ;
      RECT 0.300 20.736 32.556 20.832 ;
      RECT 0.300 21.504 32.556 21.600 ;
    END
  END VSS
  OBS
    LAYER M1 ;
    RECT 0 0 32.856 21.624 ;
    LAYER M2 ;
    RECT 0 0 32.856 21.624 ;
    LAYER M3 ;
    RECT 0 0 32.856 21.624 ;
    LAYER M4 ;
    RECT 0.072 0 32.784 21.624 ;
  END
END ctl_sram_1r1w_64x64_p192

END LIBRARY
